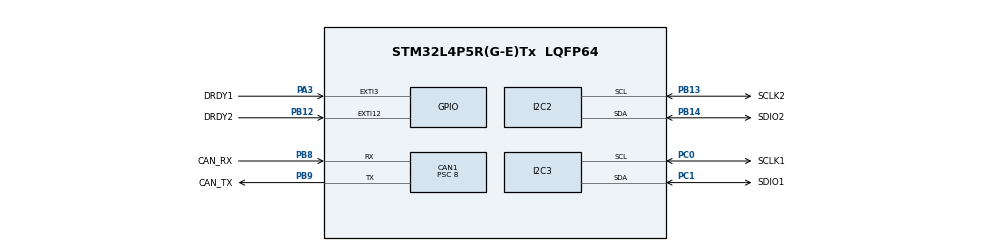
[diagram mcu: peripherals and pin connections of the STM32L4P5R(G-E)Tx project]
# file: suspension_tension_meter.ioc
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CAN1.BS1=CAN_BS1_12TQ
CAN1.BS2=CAN_BS2_2TQ
CAN1.CalculateBaudRate=533333
CAN1.CalculateTimeBit=1875
CAN1.CalculateTimeQuantum=125.0
CAN1.Prescaler=8
I2C2.Timing=0x10707DBC
I2C3.Timing=0x10707DBC
Mcu.Family=STM32L4
Mcu.Name=STM32L4P5R(G-E)Tx
Mcu.Package=LQFP64
NVIC.PriorityGroup=NVIC_PRIORITYGROUP_4
PA13\ (JTMS/SWDIO).GPIO_Label=SWDIO
PA13\ (JTMS/SWDIO).Signal=SYS_JTMS-SWDIO
PA14\ (JTCK/SWCLK).GPIO_Label=SWCLK
PA14\ (JTCK/SWCLK).Signal=SYS_JTCK-SWCLK
PA3.GPIO_Label=DRDY1
PA3.Signal=GPXTI3
PB12.GPIO_Label=DRDY2
PB12.Signal=GPXTI12
PB13.GPIO_Label=SCLK2
PB13.Mode=I2C
PB13.Signal=I2C2_SCL
PB14.GPIO_Label=SDIO2
PB14.Mode=I2C
PB14.Signal=I2C2_SDA
PB3\ (JTDO/TRACESWO).GPIO_Label=SWO
PB3\ (JTDO/TRACESWO).Signal=SYS_JTDO-SWO
PB8.GPIO_Label=CAN_RX
PB8.Mode=CAN_Activate
PB8.Signal=CAN1_RX
PB9.GPIO_Label=CAN_TX
PB9.Mode=CAN_Activate
PB9.Signal=CAN1_TX
PC0.GPIO_Label=SCLK1
PC0.Mode=I2C
PC0.Signal=I2C3_SCL
PC1.GPIO_Label=SDIO1
PC1.Mode=I2C
PC1.Signal=I2C3_SDA
PH0-OSC_IN\ (PH0).Mode=HSE-External-Oscillator
PH0-OSC_IN\ (PH0).Signal=RCC_OSC_IN
PH1-OSC_OUT\ (PH1).Mode=HSE-External-Oscillator
PH1-OSC_OUT\ (PH1).Signal=RCC_OSC_OUT
ProjectManager.HeapSize=0x200
ProjectManager.StackSize=0x400
ProjectManager.TargetToolchain=STM32CubeIDE
RCC.ADCFreq_Value=32000000
RCC.AHBFreq_Value=64000000
RCC.APB1Freq_Value=64000000
RCC.APB1TimFreq_Value=64000000
RCC.APB2Freq_Value=64000000
RCC.APB2TimFreq_Value=64000000
RCC.CortexFreq_Value=64000000
RCC.HCLKFreq_Value=64000000
RCC.HSE_VALUE=8000000
RCC.HSI48_VALUE=48000000
RCC.HSI_VALUE=16000000
RCC.LSE_VALUE=32768
RCC.MSI_VALUE=4000000
RCC.PLLN=16
RCC.PLLSourceVirtual=RCC_PLLSOURCE_HSE
RCC.SYSCLKFreq_VALUE=64000000
RCC.SYSCLKSource=RCC_SYSCLKSOURCE_PLLCLK
RCC.USBFreq_Value=32000000
RCC.VCOOutputFreq_Value=128000000
board=custom

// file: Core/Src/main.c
/* USER CODE BEGIN Header */
/**
 ******************************************************************************
 * @file           : main.c
 * @brief          : Main program body
 ******************************************************************************
 * @attention
 *
 * Copyright (c) 2023 STMicroelectronics.
 * All rights reserved.
 *
 * This software is licensed under terms that can be found in the LICENSE file
 * in the root directory of this software component.
 * If no LICENSE file comes with this software, it is provided AS-IS.
 *
 ******************************************************************************
 */
/* USER CODE END Header */
#include "main.h"
#include "can.h"
#include "i2c.h"
#include "gpio.h"

void SystemClock_Config(void);

int main(void)
{

	/* MCU Configuration--------------------------------------------------------*/

	/* Reset of all peripherals, Initializes the Flash interface and the Systick. */
	HAL_Init();

	/* Configure the system clock */
	SystemClock_Config();

	/* Initialize all configured peripherals */
	MX_GPIO_Init();
	MX_CAN1_Init();
	MX_I2C2_Init();
	MX_I2C3_Init();

	/* Infinite loop */
	while (1)
	{

	}
}

void SystemClock_Config(void)
{
	RCC_OscInitTypeDef RCC_OscInitStruct =
	{ 0 };
	RCC_ClkInitTypeDef RCC_ClkInitStruct =
	{ 0 };

	/** Configure the main internal regulator output voltage
	 */
	if (HAL_PWREx_ControlVoltageScaling(PWR_REGULATOR_VOLTAGE_SCALE1_BOOST)
			!= HAL_OK)
	{
		Error_Handler();
	}

	/** Initializes the RCC Oscillators according to the specified parameters
	 * in the RCC_OscInitTypeDef structure.
	 */
	RCC_OscInitStruct.OscillatorType = RCC_OSCILLATORTYPE_HSE;
	RCC_OscInitStruct.HSEState = RCC_HSE_ON;
	RCC_OscInitStruct.PLL.PLLState = RCC_PLL_ON;
	RCC_OscInitStruct.PLL.PLLSource = RCC_PLLSOURCE_HSE;
	RCC_OscInitStruct.PLL.PLLM = 1;
	RCC_OscInitStruct.PLL.PLLN = 30;
	RCC_OscInitStruct.PLL.PLLP = RCC_PLLP_DIV2;
	RCC_OscInitStruct.PLL.PLLQ = RCC_PLLQ_DIV2;
	RCC_OscInitStruct.PLL.PLLR = RCC_PLLR_DIV2;
	if (HAL_RCC_OscConfig(&RCC_OscInitStruct) != HAL_OK)
	{
		Error_Handler();
	}

	/** Initializes the CPU, AHB and APB buses clocks
	 */
	RCC_ClkInitStruct.ClockType = RCC_CLOCKTYPE_HCLK | RCC_CLOCKTYPE_SYSCLK
			| RCC_CLOCKTYPE_PCLK1 | RCC_CLOCKTYPE_PCLK2;
	RCC_ClkInitStruct.SYSCLKSource = RCC_SYSCLKSOURCE_PLLCLK;
	RCC_ClkInitStruct.AHBCLKDivider = RCC_SYSCLK_DIV1;
	RCC_ClkInitStruct.APB1CLKDivider = RCC_HCLK_DIV1;
	RCC_ClkInitStruct.APB2CLKDivider = RCC_HCLK_DIV1;

	if (HAL_RCC_ClockConfig(&RCC_ClkInitStruct, FLASH_LATENCY_5) != HAL_OK)
	{
		Error_Handler();
	}
}

void Error_Handler(void)
{
	__disable_irq();
	while (1)
	{
	}
}
